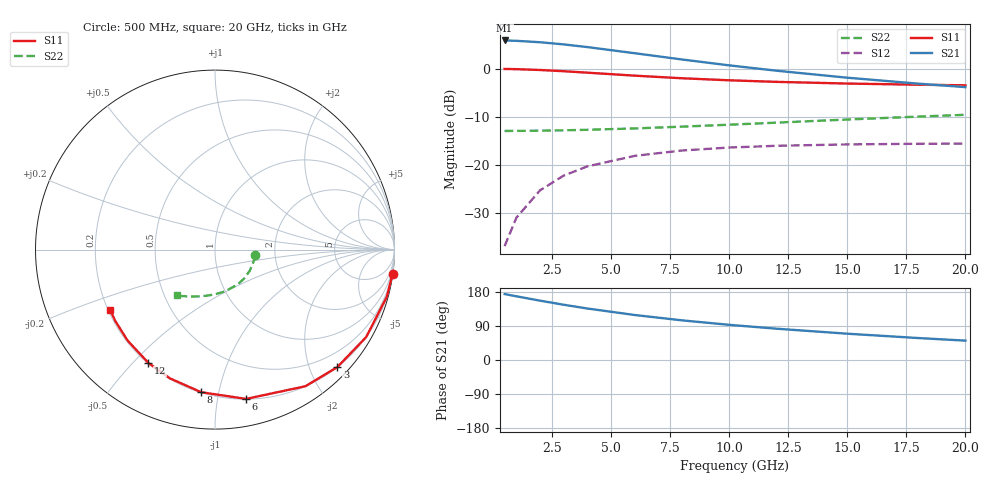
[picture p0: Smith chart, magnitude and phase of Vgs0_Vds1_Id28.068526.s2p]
# Hz S RI R 50
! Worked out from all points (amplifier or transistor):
!   12 points, 500 MHz to 20 GHz, reference 50 ohm
!   highest |S21| = 5.9 dB at 500 MHz (marker M1)
!   |S21| within 3 dB of that: start of sweep to 6.523 GHz
!   unconditionally stable (mu >= 1): 8.965 GHz to end of sweep
!   at 2 GHz: K = 0.23, MSG = 15.4 dB, |S12| = -25.3 dB
!   at 8 GHz: K = 0.90, MSG = 9.5 dB, |S12| = -17.0 dB
!   at 20 GHz: K = 2.13, MAG = -0.1 dB, |S12| = -15.6 dB
!   S11 on the Smith chart (normalised r, x): 500 MHz: 0, -15; 3 GHz: 0.20, -2.47; 6 GHz: 0.20, -1.21; 8 GHz: 0.20, -0.89; 12 GHz: 0.20, -0.55; 20 GHz: 0.21, -0.26
5e8  0.9893 -0.1332  -1.967 0.2063  0.00124 0.0141  0.223 -0.0313
1e9  0.9578 -0.2615  -1.918 0.4048  0.00488 0.0276  0.2168 -0.0617
2e9  0.8426 -0.487  -1.739 0.7533  0.0182 0.051  0.1943 -0.1168
3e9  0.6814 -0.6547  -1.488 1.011  0.0368 0.0677  0.1624 -0.161
4e9  0.5032 -0.7615  -1.211 1.174  0.0573 0.0772  0.1265 -0.194
6e9  0.1734 -0.8318  -0.7012 1.277  0.0947 0.0796  0.0569 -0.2324
8e9  -0.0769 -0.7946  -0.3175 1.212  0.1224 0.0696  -0.00125 -0.2496
1e10  -0.2515 -0.7171  -0.054 1.087  0.1408 0.0551  -0.0484 -0.2571
1.2e10  -0.3717 -0.6305  0.1228 0.9491  0.1525 0.04  -0.088 -0.2605
1.5e10  -0.4868 -0.5071  0.2845 0.757  0.1619 0.0187  -0.1391 -0.2615
1.8e10  -0.555 -0.3989  0.372 0.5944  0.1654 9.24e-05  -0.1845 -0.2587
2e10  -0.5845 -0.335  0.4056 0.5019  0.1658 -0.0109  -0.2128 -0.2545
